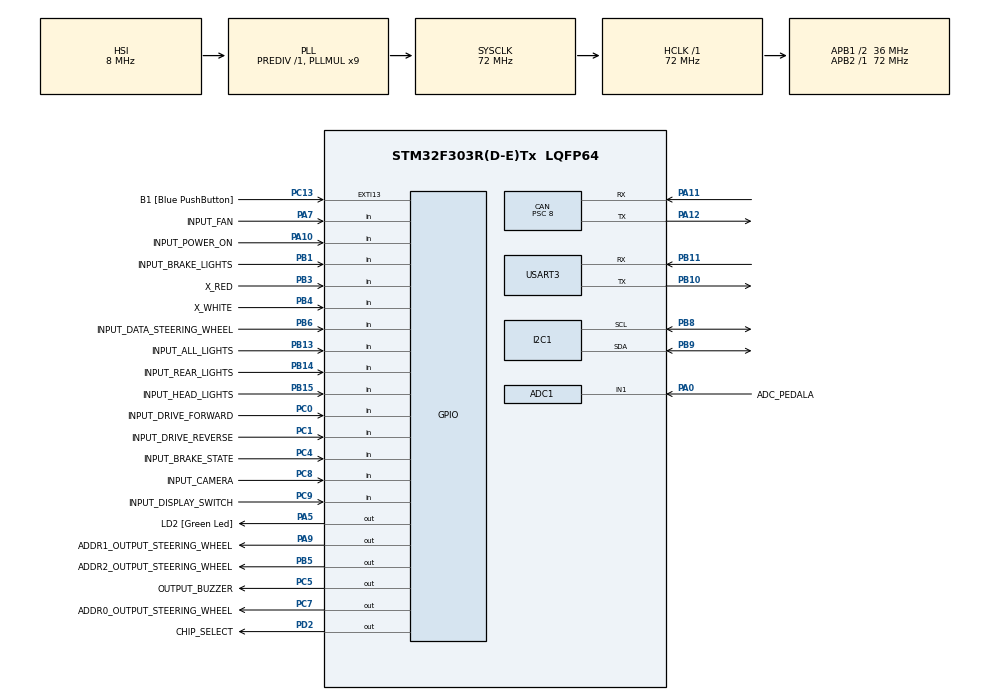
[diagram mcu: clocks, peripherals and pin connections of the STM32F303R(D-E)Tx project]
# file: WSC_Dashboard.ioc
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ADC1.Channel-0\#ChannelRegularConversion=ADC_CHANNEL_1
ADC1.NbrOfConversionFlag=1
ADC1.Offset-0\#ChannelRegularConversion=0
ADC1.OffsetNumber-0\#ChannelRegularConversion=ADC_OFFSET_NONE
ADC1.Rank-0\#ChannelRegularConversion=1
ADC1.SamplingTime-0\#ChannelRegularConversion=ADC_SAMPLETIME_1CYCLE_5
ADC1.master=1
CAN.ABOM=ENABLE
CAN.AWUM=DISABLE
CAN.BS1=CAN_BS1_15TQ
CAN.BS2=CAN_BS2_2TQ
CAN.CalculateBaudRate=250000
CAN.CalculateTimeBit=4000
CAN.CalculateTimeQuantum=222.22222222222223
CAN.NART=DISABLE
CAN.Prescaler=8
I2C1.Timing=0x00201D2B
Mcu.Family=STM32F3
Mcu.Name=STM32F303R(D-E)Tx
Mcu.Package=LQFP64
NVIC.PriorityGroup=NVIC_PRIORITYGROUP_4
NVIC.TIM6_DAC_IRQn=true\:15\:0\:false\:false\:true\:false\:true\:true
NVIC.TimeBase=TIM6_DAC_IRQn
NVIC.TimeBaseIP=TIM6
NVIC.USART3_IRQn=true\:5\:0\:true\:false\:false\:true\:true\:true
NVIC.USB_LP_CAN_RX0_IRQn=true\:5\:0\:true\:false\:false\:true\:true\:true
PA0.GPIO_Label=ADC_PEDALA
PA0.Mode=IN1-Single-Ended
PA0.Signal=ADC1_IN1
PA10.GPIO_Label=INPUT_POWER_ON
PA10.Signal=GPIO_Input
PA11.Mode=CAN_Activate
PA11.Signal=CAN_RX
PA12.Mode=CAN_Activate
PA12.Signal=CAN_TX
PA13.GPIO_Label=TMS
PA13.Mode=Serial_Wire
PA13.Signal=SYS_JTMS-SWDIO
PA14.GPIO_Label=TCK
PA14.Mode=Serial_Wire
PA14.Signal=SYS_JTCK-SWCLK
PA2.GPIO_Label=GPS_TX
PA2.GPIO_Mode=GPIO_MODE_AF_PP
PA2.GPIO_PuPd=GPIO_NOPULL
PA2.GPIO_Speed=GPIO_SPEED_FREQ_LOW
PA2.Signal=USART2_TX
PA5.GPIO_Label=LD2 [Green Led]
PA5.GPIO_Mode=GPIO_MODE_OUTPUT_PP
PA5.GPIO_PuPd=GPIO_PULLDOWN
PA5.GPIO_Speed=GPIO_SPEED_FREQ_LOW
PA5.Signal=GPIO_Output
PA7.GPIO_Label=INPUT_FAN
PA7.Signal=GPIO_Input
PA9.GPIO_Label=ADDR1_OUTPUT_STEERING_WHEEL
PA9.Signal=GPIO_Output
PB1.GPIO_Label=INPUT_BRAKE_LIGHTS
PB1.GPIO_PuPd=GPIO_PULLUP
PB1.Signal=GPIO_Input
PB10.Mode=Asynchronous
PB10.Signal=USART3_TX
PB11.Mode=Asynchronous
PB11.Signal=USART3_RX
PB13.GPIO_Label=INPUT_ALL_LIGHTS
PB13.GPIO_PuPd=GPIO_PULLDOWN
PB13.Signal=GPIO_Input
PB14.GPIO_Label=INPUT_REAR_LIGHTS
PB14.GPIO_PuPd=GPIO_PULLDOWN
PB14.Signal=GPIO_Input
PB15.GPIO_Label=INPUT_HEAD_LIGHTS
PB15.GPIO_PuPd=GPIO_PULLDOWN
PB15.Signal=GPIO_Input
PB3.GPIO_Label=X_RED
PB3.GPIO_PuPd=GPIO_PULLDOWN
PB3.Signal=GPIO_Input
PB4.GPIO_Label=X_WHITE
PB4.Signal=GPIO_Input
PB5.GPIO_Label=ADDR2_OUTPUT_STEERING_WHEEL
PB5.Signal=GPIO_Output
PB6.GPIO_Label=INPUT_DATA_STEERING_WHEEL
PB6.GPIO_PuPd=GPIO_NOPULL
PB6.Signal=GPIO_Input
PB8.Mode=I2C
PB8.Signal=I2C1_SCL
PB9.Mode=I2C
PB9.Signal=I2C1_SDA
PC0.GPIO_Label=INPUT_DRIVE_FORWARD
PC0.GPIO_PuPd=GPIO_PULLDOWN
PC0.Signal=GPIO_Input
PC1.GPIO_Label=INPUT_DRIVE_REVERSE
PC1.GPIO_PuPd=GPIO_PULLDOWN
PC1.Signal=GPIO_Input
PC13.GPIO_Label=B1 [Blue PushButton]
PC13.GPIO_ModeDefaultEXTI=GPIO_MODE_IT_FALLING
PC13.GPIO_PuPd=GPIO_PULLDOWN
PC13.Signal=GPXTI13
PC14-OSC32_IN.Signal=RCC_OSC32_IN
PC15-OSC32_OUT.Signal=RCC_OSC32_OUT
PC4.GPIO_Label=INPUT_BRAKE_STATE
PC4.GPIO_PuPd=GPIO_PULLDOWN
PC4.Signal=GPIO_Input
PC5.GPIO_Label=OUTPUT_BUZZER
PC5.Signal=GPIO_Output
PC7.GPIO_Label=ADDR0_OUTPUT_STEERING_WHEEL
PC7.Signal=GPIO_Output
PC8.GPIO_Label=INPUT_CAMERA
PC8.GPIO_PuPd=GPIO_PULLDOWN
PC8.Signal=GPIO_Input
PC9.GPIO_Label=INPUT_DISPLAY_SWITCH
PC9.GPIO_PuPd=GPIO_PULLDOWN
PC9.Signal=GPIO_Input
PD2.GPIO_Label=CHIP_SELECT
PD2.Signal=GPIO_Output
PF0-OSC_IN.Mode=HSE-External-Oscillator
PF0-OSC_IN.Signal=RCC_OSC_IN
PF1-OSC_OUT.Mode=HSE-External-Oscillator
PF1-OSC_OUT.Signal=RCC_OSC_OUT
ProjectManager.HeapSize=0x200
ProjectManager.StackSize=0x400
ProjectManager.TargetToolchain=STM32CubeIDE
RCC.AHBFreq_Value=72000000
RCC.APB1CLKDivider=RCC_HCLK_DIV2
RCC.APB1Freq_Value=36000000
RCC.APB1TimFreq_Value=72000000
RCC.APB2Freq_Value=72000000
RCC.APB2TimFreq_Value=72000000
RCC.CortexFreq_Value=72000000
RCC.HCLKFreq_Value=72000000
RCC.HSE_VALUE=8000000
RCC.HSI_VALUE=8000000
RCC.LSE_VALUE=32768
RCC.PLLM=8
RCC.PLLMUL=RCC_PLL_MUL9
RCC.PLLN=336
RCC.PLLP=RCC_PLLP_DIV4
RCC.PLLQ=7
RCC.RCC_PLLsource_Clock_Source_FROM_HSE=RCC_HSE_PREDIV_DIV2
RCC.SYSCLKFreq_VALUE=72000000
RCC.SYSCLKSourceVirtual=RCC_SYSCLKSOURCE_PLLCLK
RCC.USBFreq_Value=72000000
USART3.VirtualMode-Asynchronous=VM_ASYNC
VP_SYS_VS_tim6.Mode=TIM6
board=NUCLEO-F303RE

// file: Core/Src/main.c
/* USER CODE BEGIN Header */
/**
 ******************************************************************************
 * @file           : main.c
 * @brief          : Main program body
 ******************************************************************************
 * @attention
 *
 * Copyright (c) 2025 STMicroelectronics.
 * All rights reserved.
 *
 * This software is licensed under terms that can be found in the LICENSE file
 * in the root directory of this software component.
 * If no LICENSE file comes with this software, it is provided AS-IS.
 *
 ******************************************************************************
 */
/* USER CODE END Header */
#include "main.h"

ADC_HandleTypeDef hadc1;

CAN_HandleTypeDef hcan;

I2C_HandleTypeDef hi2c1;

UART_HandleTypeDef huart3;

void SystemClock_Config(void);
static void MX_GPIO_Init(void);
static void MX_CAN_Init(void);
static void MX_ADC1_Init(void);
static void MX_I2C1_Init(void);
static void MX_USART3_UART_Init(void);

int main(void)
{

  /* MCU Configuration--------------------------------------------------------*/

  /* Reset of all peripherals, Initializes the Flash interface and the Systick. */
  HAL_Init();

  /* Configure the system clock */
  SystemClock_Config();

  /* Initialize all configured peripherals */
  MX_GPIO_Init();
  MX_CAN_Init();
  MX_ADC1_Init();
  MX_I2C1_Init();
  MX_USART3_UART_Init();
  /* USER CODE BEGIN 2 */

	/*************************************PERIPHERAL INITIALIZATION START HERE ***********************************************/
    configASSERT(!HAL_CAN_Start(&hcan));
	Display_Init();
    Efficiency_Init();

	/*************************************PERIPHERAL INITIALIZATION END HERE ***********************************************/
#if (SEGGER_DEBUG_PROBE == 1)
	//Segger tracing start
	SEGGER_SYSVIEW_Conf();
	SEGGER_SYSVIEW_Start();
#endif

	TaskHandle_t config_handle;
	configASSERT(
			xTaskCreate((TaskFunction_t) config_handler, "config", 500, NULL, 8, &config_handle));

	vTaskStartScheduler();
  /* USER CODE END 2 */

  /* Infinite loop */
	while (1)
	{

	}
}

void SystemClock_Config(void)
{
  RCC_OscInitTypeDef RCC_OscInitStruct = {0};
  RCC_ClkInitTypeDef RCC_ClkInitStruct = {0};
  RCC_PeriphCLKInitTypeDef PeriphClkInit = {0};

  /** Initializes the RCC Oscillators according to the specified parameters
  * in the RCC_OscInitTypeDef structure.
  */
  RCC_OscInitStruct.OscillatorType = RCC_OSCILLATORTYPE_HSI;
  RCC_OscInitStruct.HSIState = RCC_HSI_ON;
  RCC_OscInitStruct.HSICalibrationValue = RCC_HSICALIBRATION_DEFAULT;
  RCC_OscInitStruct.PLL.PLLState = RCC_PLL_ON;
  RCC_OscInitStruct.PLL.PLLSource = RCC_PLLSOURCE_HSI;
  RCC_OscInitStruct.PLL.PLLMUL = RCC_PLL_MUL9;
  RCC_OscInitStruct.PLL.PREDIV = RCC_PREDIV_DIV1;
  if (HAL_RCC_OscConfig(&RCC_OscInitStruct) != HAL_OK)
  {
    Error_Handler();
  }

  /** Initializes the CPU, AHB and APB buses clocks
  */
  RCC_ClkInitStruct.ClockType = RCC_CLOCKTYPE_HCLK|RCC_CLOCKTYPE_SYSCLK
                              |RCC_CLOCKTYPE_PCLK1|RCC_CLOCKTYPE_PCLK2;
  RCC_ClkInitStruct.SYSCLKSource = RCC_SYSCLKSOURCE_PLLCLK;
  RCC_ClkInitStruct.AHBCLKDivider = RCC_SYSCLK_DIV1;
  RCC_ClkInitStruct.APB1CLKDivider = RCC_HCLK_DIV2;
  RCC_ClkInitStruct.APB2CLKDivider = RCC_HCLK_DIV1;

  if (HAL_RCC_ClockConfig(&RCC_ClkInitStruct, FLASH_LATENCY_2) != HAL_OK)
  {
    Error_Handler();
  }
  PeriphClkInit.PeriphClockSelection = RCC_PERIPHCLK_USART3|RCC_PERIPHCLK_I2C1
                              |RCC_PERIPHCLK_ADC12;
  PeriphClkInit.Usart3ClockSelection = RCC_USART3CLKSOURCE_PCLK1;
  PeriphClkInit.Adc12ClockSelection = RCC_ADC12PLLCLK_DIV1;
  PeriphClkInit.I2c1ClockSelection = RCC_I2C1CLKSOURCE_HSI;
  if (HAL_RCCEx_PeriphCLKConfig(&PeriphClkInit) != HAL_OK)
  {
    Error_Handler();
  }
}

static void MX_ADC1_Init(void)
{

  ADC_MultiModeTypeDef multimode = {0};
  ADC_ChannelConfTypeDef sConfig = {0};

  /** Common config
  */
  hadc1.Instance = ADC1;
  hadc1.Init.ClockPrescaler = ADC_CLOCK_ASYNC_DIV1;
  hadc1.Init.Resolution = ADC_RESOLUTION_12B;
  hadc1.Init.ScanConvMode = ADC_SCAN_DISABLE;
  hadc1.Init.ContinuousConvMode = DISABLE;
  hadc1.Init.DiscontinuousConvMode = DISABLE;
  hadc1.Init.ExternalTrigConvEdge = ADC_EXTERNALTRIGCONVEDGE_NONE;
  hadc1.Init.ExternalTrigConv = ADC_SOFTWARE_START;
  hadc1.Init.DataAlign = ADC_DATAALIGN_RIGHT;
  hadc1.Init.NbrOfConversion = 1;
  hadc1.Init.DMAContinuousRequests = DISABLE;
  hadc1.Init.EOCSelection = ADC_EOC_SINGLE_CONV;
  hadc1.Init.LowPowerAutoWait = DISABLE;
  hadc1.Init.Overrun = ADC_OVR_DATA_OVERWRITTEN;
  if (HAL_ADC_Init(&hadc1) != HAL_OK)
  {
    Error_Handler();
  }

  /** Configure the ADC multi-mode
  */
  multimode.Mode = ADC_MODE_INDEPENDENT;
  if (HAL_ADCEx_MultiModeConfigChannel(&hadc1, &multimode) != HAL_OK)
  {
    Error_Handler();
  }

  /** Configure Regular Channel
  */
  sConfig.Channel = ADC_CHANNEL_1;
  sConfig.Rank = ADC_REGULAR_RANK_1;
  sConfig.SingleDiff = ADC_SINGLE_ENDED;
  sConfig.SamplingTime = ADC_SAMPLETIME_1CYCLE_5;
  sConfig.OffsetNumber = ADC_OFFSET_NONE;
  sConfig.Offset = 0;
  if (HAL_ADC_ConfigChannel(&hadc1, &sConfig) != HAL_OK)
  {
    Error_Handler();
  }

}

static void MX_CAN_Init(void)
{

  hcan.Instance = CAN;
  hcan.Init.Prescaler = 8;
  hcan.Init.Mode = CAN_MODE_NORMAL;
  hcan.Init.SyncJumpWidth = CAN_SJW_1TQ;
  hcan.Init.TimeSeg1 = CAN_BS1_15TQ;
  hcan.Init.TimeSeg2 = CAN_BS2_2TQ;
  hcan.Init.TimeTriggeredMode = DISABLE;
  hcan.Init.AutoBusOff = ENABLE;
  hcan.Init.AutoWakeUp = DISABLE;
  hcan.Init.AutoRetransmission = DISABLE;
  hcan.Init.ReceiveFifoLocked = DISABLE;
  hcan.Init.TransmitFifoPriority = DISABLE;
  if (HAL_CAN_Init(&hcan) != HAL_OK)
  {
    Error_Handler();
  }
  /* USER CODE BEGIN CAN_Init 2 */
	CAN_FilterTypeDef canfilterconfig;

	canfilterconfig.FilterActivation = CAN_FILTER_ENABLE;
	canfilterconfig.FilterBank = 10;
	canfilterconfig.FilterFIFOAssignment = CAN_RX_FIFO0;
	canfilterconfig.FilterIdHigh = 0; //this tells what to compare the incoming data to
	canfilterconfig.FilterIdLow = 0x0000;
	canfilterconfig.FilterMaskIdHigh = 0; //this tells which bits to compare
	canfilterconfig.FilterMaskIdLow = 0x0000;
	canfilterconfig.FilterMode = CAN_FILTERMODE_IDMASK;
	canfilterconfig.FilterScale = CAN_FILTERSCALE_32BIT;
	canfilterconfig.SlaveStartFilterBank = 10;

	HAL_CAN_ConfigFilter(&hcan, &canfilterconfig);
  /* USER CODE END CAN_Init 2 */

}

static void MX_I2C1_Init(void)
{

  hi2c1.Instance = I2C1;
  hi2c1.Init.Timing = 0x00201D2B;
  hi2c1.Init.OwnAddress1 = 0;
  hi2c1.Init.AddressingMode = I2C_ADDRESSINGMODE_7BIT;
  hi2c1.Init.DualAddressMode = I2C_DUALADDRESS_DISABLE;
  hi2c1.Init.OwnAddress2 = 0;
  hi2c1.Init.OwnAddress2Masks = I2C_OA2_NOMASK;
  hi2c1.Init.GeneralCallMode = I2C_GENERALCALL_DISABLE;
  hi2c1.Init.NoStretchMode = I2C_NOSTRETCH_DISABLE;
  if (HAL_I2C_Init(&hi2c1) != HAL_OK)
  {
    Error_Handler();
  }

  /** Configure Analogue filter
  */
  if (HAL_I2CEx_ConfigAnalogFilter(&hi2c1, I2C_ANALOGFILTER_ENABLE) != HAL_OK)
  {
    Error_Handler();
  }

  /** Configure Digital filter
  */
  if (HAL_I2CEx_ConfigDigitalFilter(&hi2c1, 0) != HAL_OK)
  {
    Error_Handler();
  }

}

static void MX_USART3_UART_Init(void)
{

  huart3.Instance = USART3;
  huart3.Init.BaudRate = 38400;
  huart3.Init.WordLength = UART_WORDLENGTH_8B;
  huart3.Init.StopBits = UART_STOPBITS_1;
  huart3.Init.Parity = UART_PARITY_NONE;
  huart3.Init.Mode = UART_MODE_TX_RX;
  huart3.Init.HwFlowCtl = UART_HWCONTROL_NONE;
  huart3.Init.OverSampling = UART_OVERSAMPLING_16;
  huart3.Init.OneBitSampling = UART_ONE_BIT_SAMPLE_DISABLE;
  huart3.AdvancedInit.AdvFeatureInit = UART_ADVFEATURE_NO_INIT;
  if (HAL_UART_Init(&huart3) != HAL_OK)
  {
    Error_Handler();
  }

}

static void MX_GPIO_Init(void)
{
  GPIO_InitTypeDef GPIO_InitStruct = {0};

  /* GPIO Ports Clock Enable */
  __HAL_RCC_GPIOC_CLK_ENABLE();
  __HAL_RCC_GPIOF_CLK_ENABLE();
  __HAL_RCC_GPIOA_CLK_ENABLE();
  __HAL_RCC_GPIOB_CLK_ENABLE();
  __HAL_RCC_GPIOD_CLK_ENABLE();

  /*Configure GPIO pin Output Level */
  HAL_GPIO_WritePin(GPIOA, LD2_Pin|ADDR1_OUTPUT_STEERING_WHEEL_Pin, GPIO_PIN_RESET);

  /*Configure GPIO pin Output Level */
  HAL_GPIO_WritePin(GPIOC, OUTPUT_BUZZER_Pin|ADDR0_OUTPUT_STEERING_WHEEL_Pin, GPIO_PIN_RESET);

  /*Configure GPIO pin Output Level */
  HAL_GPIO_WritePin(CHIP_SELECT_GPIO_Port, CHIP_SELECT_Pin, GPIO_PIN_RESET);

  /*Configure GPIO pin Output Level */
  HAL_GPIO_WritePin(ADDR2_OUTPUT_STEERING_WHEEL_GPIO_Port, ADDR2_OUTPUT_STEERING_WHEEL_Pin, GPIO_PIN_RESET);

  /*Configure GPIO pin : B1_Pin */
  GPIO_InitStruct.Pin = B1_Pin;
  GPIO_InitStruct.Mode = GPIO_MODE_IT_FALLING;
  GPIO_InitStruct.Pull = GPIO_PULLDOWN;
  HAL_GPIO_Init(B1_GPIO_Port, &GPIO_InitStruct);

  /*Configure GPIO pins : INPUT_DRIVE_FORWARD_Pin INPUT_DRIVE_REVERSE_Pin INPUT_BRAKE_STATE_Pin INPUT_CAMERA_Pin
                           INPUT_DISPLAY_SWITCH_Pin */
  GPIO_InitStruct.Pin = INPUT_DRIVE_FORWARD_Pin|INPUT_DRIVE_REVERSE_Pin|INPUT_BRAKE_STATE_Pin|INPUT_CAMERA_Pin
                          |INPUT_DISPLAY_SWITCH_Pin;
  GPIO_InitStruct.Mode = GPIO_MODE_INPUT;
  GPIO_InitStruct.Pull = GPIO_PULLDOWN;
  HAL_GPIO_Init(GPIOC, &GPIO_InitStruct);

  /*Configure GPIO pin : GPS_TX_Pin */
  GPIO_InitStruct.Pin = GPS_TX_Pin;
  GPIO_InitStruct.Mode = GPIO_MODE_AF_PP;
  GPIO_InitStruct.Pull = GPIO_NOPULL;
  GPIO_InitStruct.Speed = GPIO_SPEED_FREQ_LOW;
  GPIO_InitStruct.Alternate = GPIO_AF7_USART2;
  HAL_GPIO_Init(GPS_TX_GPIO_Port, &GPIO_InitStruct);

  /*Configure GPIO pin : LD2_Pin */
  GPIO_InitStruct.Pin = LD2_Pin;
  GPIO_InitStruct.Mode = GPIO_MODE_OUTPUT_PP;
  GPIO_InitStruct.Pull = GPIO_PULLDOWN;
  GPIO_InitStruct.Speed = GPIO_SPEED_FREQ_LOW;
  HAL_GPIO_Init(LD2_GPIO_Port, &GPIO_InitStruct);

  /*Configure GPIO pins : INPUT_CRUISE_DOWN_Pin INPUT_FAN_Pin */
  GPIO_InitStruct.Pin = INPUT_CRUISE_DOWN_Pin|INPUT_FAN_Pin;
  GPIO_InitStruct.Mode = GPIO_MODE_INPUT;
  GPIO_InitStruct.Pull = GPIO_PULLDOWN;
  HAL_GPIO_Init(GPIOA, &GPIO_InitStruct);

  /*Configure GPIO pins : OUTPUT_BUZZER_Pin ADDR0_OUTPUT_STEERING_WHEEL_Pin */
  GPIO_InitStruct.Pin = OUTPUT_BUZZER_Pin|ADDR0_OUTPUT_STEERING_WHEEL_Pin;
  GPIO_InitStruct.Mode = GPIO_MODE_OUTPUT_PP;
  GPIO_InitStruct.Pull = GPIO_NOPULL;
  GPIO_InitStruct.Speed = GPIO_SPEED_FREQ_LOW;
  HAL_GPIO_Init(GPIOC, &GPIO_InitStruct);

  /*Configure GPIO pin : INPUT_BRAKE_LIGHTS_Pin */
  GPIO_InitStruct.Pin = INPUT_BRAKE_LIGHTS_Pin;
  GPIO_InitStruct.Mode = GPIO_MODE_INPUT;
  GPIO_InitStruct.Pull = GPIO_PULLUP;
  HAL_GPIO_Init(INPUT_BRAKE_LIGHTS_GPIO_Port, &GPIO_InitStruct);

  /*Configure GPIO pins : INPUT_ALL_LIGHTS_Pin INPUT_REAR_LIGHTS_Pin INPUT_HEAD_LIGHTS_Pin INPUT_HORN_Pin */
  GPIO_InitStruct.Pin = INPUT_ALL_LIGHTS_Pin|INPUT_REAR_LIGHTS_Pin|INPUT_HEAD_LIGHTS_Pin|INPUT_HORN_Pin;
  GPIO_InitStruct.Mode = GPIO_MODE_INPUT;
  GPIO_InitStruct.Pull = GPIO_PULLDOWN;
  HAL_GPIO_Init(GPIOB, &GPIO_InitStruct);

  /*Configure GPIO pin : ADDR1_OUTPUT_STEERING_WHEEL_Pin */
  GPIO_InitStruct.Pin = ADDR1_OUTPUT_STEERING_WHEEL_Pin;
  GPIO_InitStruct.Mode = GPIO_MODE_OUTPUT_PP;
  GPIO_InitStruct.Pull = GPIO_NOPULL;
  GPIO_InitStruct.Speed = GPIO_SPEED_FREQ_LOW;
  HAL_GPIO_Init(ADDR1_OUTPUT_STEERING_WHEEL_GPIO_Port, &GPIO_InitStruct);

  /*Configure GPIO pin : INPUT_POWER_ON_Pin */
  GPIO_InitStruct.Pin = INPUT_POWER_ON_Pin;
  GPIO_InitStruct.Mode = GPIO_MODE_INPUT;
  GPIO_InitStruct.Pull = GPIO_NOPULL;
  HAL_GPIO_Init(INPUT_POWER_ON_GPIO_Port, &GPIO_InitStruct);

  /*Configure GPIO pin : CHIP_SELECT_Pin */
  GPIO_InitStruct.Pin = CHIP_SELECT_Pin;
  GPIO_InitStruct.Mode = GPIO_MODE_OUTPUT_PP;
  GPIO_InitStruct.Pull = GPIO_NOPULL;
  GPIO_InitStruct.Speed = GPIO_SPEED_FREQ_LOW;
  HAL_GPIO_Init(CHIP_SELECT_GPIO_Port, &GPIO_InitStruct);

  /*Configure GPIO pin : ADDR2_OUTPUT_STEERING_WHEEL_Pin */
  GPIO_InitStruct.Pin = ADDR2_OUTPUT_STEERING_WHEEL_Pin;
  GPIO_InitStruct.Mode = GPIO_MODE_OUTPUT_PP;
  GPIO_InitStruct.Pull = GPIO_NOPULL;
  GPIO_InitStruct.Speed = GPIO_SPEED_FREQ_LOW;
  HAL_GPIO_Init(ADDR2_OUTPUT_STEERING_WHEEL_GPIO_Port, &GPIO_InitStruct);

  /*Configure GPIO pin : INPUT_DATA_STEERING_WHEEL_Pin */
  GPIO_InitStruct.Pin = INPUT_DATA_STEERING_WHEEL_Pin;
  GPIO_InitStruct.Mode = GPIO_MODE_INPUT;
  GPIO_InitStruct.Pull = GPIO_NOPULL;
  HAL_GPIO_Init(INPUT_DATA_STEERING_WHEEL_GPIO_Port, &GPIO_InitStruct);

}

void HAL_TIM_PeriodElapsedCallback(TIM_HandleTypeDef *htim)
{
  if (htim->Instance == TIM6) {
    HAL_IncTick();
  }
}

void Error_Handler(void)
{
	__disable_irq();
	while (1)
	{
	}
}
